! (c) 2009  Infineon Technologies AG, Munich
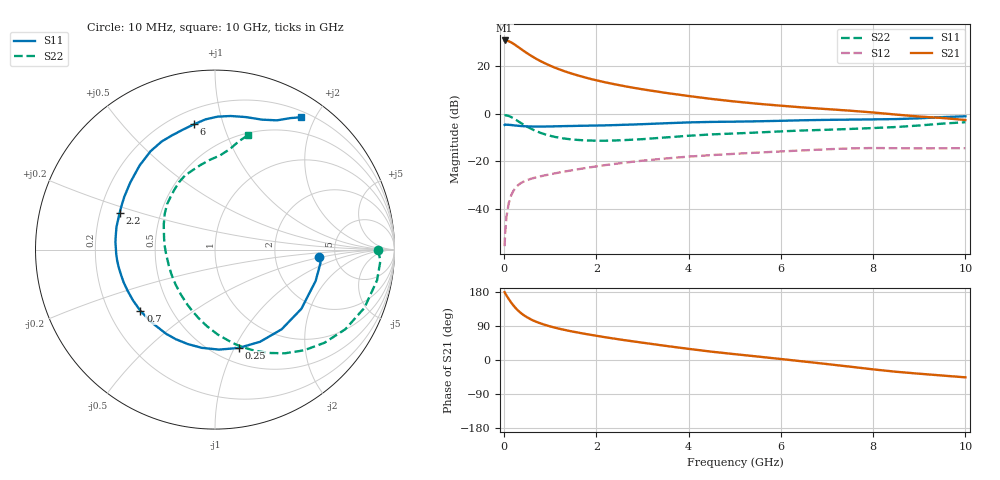
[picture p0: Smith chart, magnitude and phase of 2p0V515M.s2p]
! Infineon Technologies  Discrete & RF Semiconductors
! BFP420
! VCE =  0.5 V,  IC =  15 mA
! Common Emitter S-Parameters:  Nov 2009
# GHz  S  MA  R  50
!  f  S11  S21  S12  S22
! GHz  MAG  ANG  MAG  ANG  MAG  ANG  MAG  ANG
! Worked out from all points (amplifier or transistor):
!   46 points, 10 MHz to 10 GHz, reference 50 ohm
!   highest |S21| = 30.6 dB at 10 MHz (marker M1)
!   |S21| within 3 dB of that: start of sweep to 323.2 MHz
!   unconditionally stable (mu >= 1): 1.86 GHz to end of sweep
!   at 300 MHz: K = 0.28, MSG = 28.9 dB, |S12| = -29.9 dB
!   at 1.7 GHz: K = 0.96, MSG = 19.2 dB, |S12| = -22.9 dB
!   at 10 GHz: K = 1.05, MAG = 4.6 dB, |S12| = -14.4 dB
!   lowest NFmin = 1.06 dB at 900 MHz
!   S11 on the Smith chart (normalised r, x): 10 MHz: 3.71, -0.43; 250 MHz: 0.65, -1.04; 700 MHz: 0.34, -0.32; 2.2 GHz: 0.28, +0.17; 6 GHz: 0.29, +0.81; 10 GHz: 0.28, +1.81
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0.01  0.5803 -3.8  33.81 179.2  0.0017 111.6  0.9091 0.0
0.05  0.5873 -17.3  33.45 170.4  0.007 83.0  0.919 -10.7
0.1  0.5834 -34.5  32.58 160.8  0.0135 76.2  0.8934 -21.3
0.15  0.5788 -50.1  30.87 151.9  0.0194 69.9  0.8511 -31.4
0.2  0.5716 -64.0  28.93 144.0  0.0243 64.4  0.8009 -40.4
0.25  0.5637 -76.4  26.8 136.9  0.0285 59.8  0.7492 -48.5
0.3  0.5576 -87.7  24.83 130.7  0.0319 56.0  0.6968 -56.0
0.35  0.5523 -97.5  22.95 125.3  0.0348 52.9  0.6492 -62.5
0.45  0.5449 -113.5  19.64 116.3  0.0392 48.5  0.5663 -74.0
0.6  0.5382 -131.5  15.84 105.9  0.0441 44.6  0.4738 -88.1
0.7  0.5376 -140.7  13.91 100.6  0.0468 43.2  0.4286 -96.1
0.9  0.5382 -154.7  11.09 92.1  0.0517 41.8  0.3656 -110.0
1.1  0.5424 -165.4  9.141 85.4  0.0565 41.2  0.3263 -122.1
1.4  0.551 -177.6  7.183 77.1  0.0638 40.6  0.294 -138.0
1.7  0.558 172.6  5.893 70.2  0.0713 39.8  0.2782 -151.3
2.2  0.569 159.2  4.496 59.9  0.0842 37.7  0.2714 -169.9
3.5  0.6293 131.9  2.718 37.3  0.1155 28.3  0.3179 153.9
5.5  0.6915 105.1  1.608 9.1  0.1534 11.5  0.4033 124.1
6  0.7082 99.4  1.464 2.6  0.1622 7.4  0.4258 118.1
7  0.7409 88.9  1.243 -10.7  0.18 -2.2  0.4599 105.6
8.5  0.7697 70.2  0.955 -31.1  0.1895 -18.9  0.5252 87.0
10  0.8801 56.9  0.736 -45.7  0.1897 -29.3  0.6618 74.0
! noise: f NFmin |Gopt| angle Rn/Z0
0.9  1.06  0.09  -152  0.13
1.8  1.36  0.18  -147  0.12
2.4  1.49  0.17  -148  0.14
3  1.53  0.25  -138  0.14
4  1.67  0.38  -119  0.2
5  2.14  0.44  -103  0.32
6  2.48  0.5  -88  0.47
